VERSION 5.7 ;
BUSBITCHARS "[]" ;
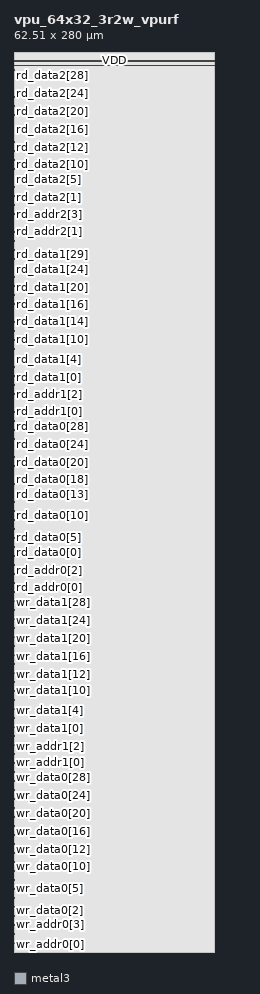
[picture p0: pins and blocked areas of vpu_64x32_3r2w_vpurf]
MACRO vpu_64x32_3r2w_vpurf
  FOREIGN vpu_64x32_3r2w_vpurf 0 0 ;
  SYMMETRY X Y R90 ;
  SIZE 62.510 BY 280.000 ;
  CLASS BLOCK ;
  PIN clk
    DIRECTION INPUT ;
    USE SIGNAL ;
    SHAPE ABUTMENT ;
    PORT
      LAYER metal3 ;
      RECT 0.000 1.400 0.140 1.540 ;
    END
  END clk
  PIN wr_enable0
    DIRECTION INPUT ;
    USE SIGNAL ;
    SHAPE ABUTMENT ;
    PORT
      LAYER metal3 ;
      RECT 0.000 2.800 0.140 2.940 ;
    END
  END wr_enable0
  PIN wr_addr0[0]
    DIRECTION INPUT ;
    USE SIGNAL ;
    SHAPE ABUTMENT ;
    PORT
      LAYER metal3 ;
      RECT 0.000 4.200 0.140 4.340 ;
    END
  END wr_addr0[0]
  PIN wr_addr0[1]
    DIRECTION INPUT ;
    USE SIGNAL ;
    SHAPE ABUTMENT ;
    PORT
      LAYER metal3 ;
      RECT 0.000 5.600 0.140 5.740 ;
    END
  END wr_addr0[1]
  PIN wr_addr0[2]
    DIRECTION INPUT ;
    USE SIGNAL ;
    SHAPE ABUTMENT ;
    PORT
      LAYER metal3 ;
      RECT 0.000 7.000 0.140 7.140 ;
    END
  END wr_addr0[2]
  PIN wr_addr0[3]
    DIRECTION INPUT ;
    USE SIGNAL ;
    SHAPE ABUTMENT ;
    PORT
      LAYER metal3 ;
      RECT 0.000 8.400 0.140 8.540 ;
    END
  END wr_addr0[3]
  PIN wr_addr0[4]
    DIRECTION INPUT ;
    USE SIGNAL ;
    SHAPE ABUTMENT ;
    PORT
      LAYER metal3 ;
      RECT 0.000 9.800 0.140 9.940 ;
    END
  END wr_addr0[4]
  PIN wr_addr0[5]
    DIRECTION INPUT ;
    USE SIGNAL ;
    SHAPE ABUTMENT ;
    PORT
      LAYER metal3 ;
      RECT 0.000 11.200 0.140 11.340 ;
    END
  END wr_addr0[5]
  PIN wr_data0[0]
    DIRECTION INPUT ;
    USE SIGNAL ;
    SHAPE ABUTMENT ;
    PORT
      LAYER metal3 ;
      RECT 0.000 12.600 0.140 12.740 ;
    END
  END wr_data0[0]
  PIN wr_data0[1]
    DIRECTION INPUT ;
    USE SIGNAL ;
    SHAPE ABUTMENT ;
    PORT
      LAYER metal3 ;
      RECT 0.000 14.000 0.140 14.140 ;
    END
  END wr_data0[1]
  PIN wr_data0[2]
    DIRECTION INPUT ;
    USE SIGNAL ;
    SHAPE ABUTMENT ;
    PORT
      LAYER metal3 ;
      RECT 0.000 15.400 0.140 15.540 ;
    END
  END wr_data0[2]
  PIN wr_data0[3]
    DIRECTION INPUT ;
    USE SIGNAL ;
    SHAPE ABUTMENT ;
    PORT
      LAYER metal3 ;
      RECT 0.000 16.800 0.140 16.940 ;
    END
  END wr_data0[3]
  PIN wr_data0[4]
    DIRECTION INPUT ;
    USE SIGNAL ;
    SHAPE ABUTMENT ;
    PORT
      LAYER metal3 ;
      RECT 0.000 18.200 0.140 18.340 ;
    END
  END wr_data0[4]
  PIN wr_data0[5]
    DIRECTION INPUT ;
    USE SIGNAL ;
    SHAPE ABUTMENT ;
    PORT
      LAYER metal3 ;
      RECT 0.000 19.600 0.140 19.740 ;
    END
  END wr_data0[5]
  PIN wr_data0[6]
    DIRECTION INPUT ;
    USE SIGNAL ;
    SHAPE ABUTMENT ;
    PORT
      LAYER metal3 ;
      RECT 0.000 21.000 0.140 21.140 ;
    END
  END wr_data0[6]
  PIN wr_data0[7]
    DIRECTION INPUT ;
    USE SIGNAL ;
    SHAPE ABUTMENT ;
    PORT
      LAYER metal3 ;
      RECT 0.000 22.400 0.140 22.540 ;
    END
  END wr_data0[7]
  PIN wr_data0[8]
    DIRECTION INPUT ;
    USE SIGNAL ;
    SHAPE ABUTMENT ;
    PORT
      LAYER metal3 ;
      RECT 0.000 23.800 0.140 23.940 ;
    END
  END wr_data0[8]
  PIN wr_data0[9]
    DIRECTION INPUT ;
    USE SIGNAL ;
    SHAPE ABUTMENT ;
    PORT
      LAYER metal3 ;
      RECT 0.000 25.200 0.140 25.340 ;
    END
  END wr_data0[9]
  PIN wr_data0[10]
    DIRECTION INPUT ;
    USE SIGNAL ;
    SHAPE ABUTMENT ;
    PORT
      LAYER metal3 ;
      RECT 0.000 26.600 0.140 26.740 ;
    END
  END wr_data0[10]
  PIN wr_data0[11]
    DIRECTION INPUT ;
    USE SIGNAL ;
    SHAPE ABUTMENT ;
    PORT
      LAYER metal3 ;
      RECT 0.000 28.000 0.140 28.140 ;
    END
  END wr_data0[11]
  PIN wr_data0[12]
    DIRECTION INPUT ;
    USE SIGNAL ;
    SHAPE ABUTMENT ;
    PORT
      LAYER metal3 ;
      RECT 0.000 29.400 0.140 29.540 ;
    END
  END wr_data0[12]
  PIN wr_data0[13]
    DIRECTION INPUT ;
    USE SIGNAL ;
    SHAPE ABUTMENT ;
    PORT
      LAYER metal3 ;
      RECT 0.000 30.800 0.140 30.940 ;
    END
  END wr_data0[13]
  PIN wr_data0[14]
    DIRECTION INPUT ;
    USE SIGNAL ;
    SHAPE ABUTMENT ;
    PORT
      LAYER metal3 ;
      RECT 0.000 32.200 0.140 32.340 ;
    END
  END wr_data0[14]
  PIN wr_data0[15]
    DIRECTION INPUT ;
    USE SIGNAL ;
    SHAPE ABUTMENT ;
    PORT
      LAYER metal3 ;
      RECT 0.000 33.600 0.140 33.740 ;
    END
  END wr_data0[15]
  PIN wr_data0[16]
    DIRECTION INPUT ;
    USE SIGNAL ;
    SHAPE ABUTMENT ;
    PORT
      LAYER metal3 ;
      RECT 0.000 35.000 0.140 35.140 ;
    END
  END wr_data0[16]
  PIN wr_data0[17]
    DIRECTION INPUT ;
    USE SIGNAL ;
    SHAPE ABUTMENT ;
    PORT
      LAYER metal3 ;
      RECT 0.000 36.400 0.140 36.540 ;
    END
  END wr_data0[17]
  PIN wr_data0[18]
    DIRECTION INPUT ;
    USE SIGNAL ;
    SHAPE ABUTMENT ;
    PORT
      LAYER metal3 ;
      RECT 0.000 37.800 0.140 37.940 ;
    END
  END wr_data0[18]
  PIN wr_data0[19]
    DIRECTION INPUT ;
    USE SIGNAL ;
    SHAPE ABUTMENT ;
    PORT
      LAYER metal3 ;
      RECT 0.000 39.200 0.140 39.340 ;
    END
  END wr_data0[19]
  PIN wr_data0[20]
    DIRECTION INPUT ;
    USE SIGNAL ;
    SHAPE ABUTMENT ;
    PORT
      LAYER metal3 ;
      RECT 0.000 40.600 0.140 40.740 ;
    END
  END wr_data0[20]
  PIN wr_data0[21]
    DIRECTION INPUT ;
    USE SIGNAL ;
    SHAPE ABUTMENT ;
    PORT
      LAYER metal3 ;
      RECT 0.000 42.000 0.140 42.140 ;
    END
  END wr_data0[21]
  PIN wr_data0[22]
    DIRECTION INPUT ;
    USE SIGNAL ;
    SHAPE ABUTMENT ;
    PORT
      LAYER metal3 ;
      RECT 0.000 43.400 0.140 43.540 ;
    END
  END wr_data0[22]
  PIN wr_data0[23]
    DIRECTION INPUT ;
    USE SIGNAL ;
    SHAPE ABUTMENT ;
    PORT
      LAYER metal3 ;
      RECT 0.000 44.800 0.140 44.940 ;
    END
  END wr_data0[23]
  PIN wr_data0[24]
    DIRECTION INPUT ;
    USE SIGNAL ;
    SHAPE ABUTMENT ;
    PORT
      LAYER metal3 ;
      RECT 0.000 46.200 0.140 46.340 ;
    END
  END wr_data0[24]
  PIN wr_data0[25]
    DIRECTION INPUT ;
    USE SIGNAL ;
    SHAPE ABUTMENT ;
    PORT
      LAYER metal3 ;
      RECT 0.000 47.600 0.140 47.740 ;
    END
  END wr_data0[25]
  PIN wr_data0[26]
    DIRECTION INPUT ;
    USE SIGNAL ;
    SHAPE ABUTMENT ;
    PORT
      LAYER metal3 ;
      RECT 0.000 49.000 0.140 49.140 ;
    END
  END wr_data0[26]
  PIN wr_data0[27]
    DIRECTION INPUT ;
    USE SIGNAL ;
    SHAPE ABUTMENT ;
    PORT
      LAYER metal3 ;
      RECT 0.000 50.400 0.140 50.540 ;
    END
  END wr_data0[27]
  PIN wr_data0[28]
    DIRECTION INPUT ;
    USE SIGNAL ;
    SHAPE ABUTMENT ;
    PORT
      LAYER metal3 ;
      RECT 0.000 51.800 0.140 51.940 ;
    END
  END wr_data0[28]
  PIN wr_data0[29]
    DIRECTION INPUT ;
    USE SIGNAL ;
    SHAPE ABUTMENT ;
    PORT
      LAYER metal3 ;
      RECT 0.000 53.200 0.140 53.340 ;
    END
  END wr_data0[29]
  PIN wr_data0[30]
    DIRECTION INPUT ;
    USE SIGNAL ;
    SHAPE ABUTMENT ;
    PORT
      LAYER metal3 ;
      RECT 0.000 54.600 0.140 54.740 ;
    END
  END wr_data0[30]
  PIN wr_data0[31]
    DIRECTION INPUT ;
    USE SIGNAL ;
    SHAPE ABUTMENT ;
    PORT
      LAYER metal3 ;
      RECT 0.000 56.000 0.140 56.140 ;
    END
  END wr_data0[31]
  PIN wr_enable1
    DIRECTION INPUT ;
    USE SIGNAL ;
    SHAPE ABUTMENT ;
    PORT
      LAYER metal3 ;
      RECT 0.000 57.400 0.140 57.540 ;
    END
  END wr_enable1
  PIN wr_addr1[0]
    DIRECTION INPUT ;
    USE SIGNAL ;
    SHAPE ABUTMENT ;
    PORT
      LAYER metal3 ;
      RECT 0.000 58.800 0.140 58.940 ;
    END
  END wr_addr1[0]
  PIN wr_addr1[1]
    DIRECTION INPUT ;
    USE SIGNAL ;
    SHAPE ABUTMENT ;
    PORT
      LAYER metal3 ;
      RECT 0.000 60.200 0.140 60.340 ;
    END
  END wr_addr1[1]
  PIN wr_addr1[2]
    DIRECTION INPUT ;
    USE SIGNAL ;
    SHAPE ABUTMENT ;
    PORT
      LAYER metal3 ;
      RECT 0.000 61.600 0.140 61.740 ;
    END
  END wr_addr1[2]
  PIN wr_addr1[3]
    DIRECTION INPUT ;
    USE SIGNAL ;
    SHAPE ABUTMENT ;
    PORT
      LAYER metal3 ;
      RECT 0.000 63.000 0.140 63.140 ;
    END
  END wr_addr1[3]
  PIN wr_addr1[4]
    DIRECTION INPUT ;
    USE SIGNAL ;
    SHAPE ABUTMENT ;
    PORT
      LAYER metal3 ;
      RECT 0.000 64.400 0.140 64.540 ;
    END
  END wr_addr1[4]
  PIN wr_addr1[5]
    DIRECTION INPUT ;
    USE SIGNAL ;
    SHAPE ABUTMENT ;
    PORT
      LAYER metal3 ;
      RECT 0.000 65.800 0.140 65.940 ;
    END
  END wr_addr1[5]
  PIN wr_data1[0]
    DIRECTION INPUT ;
    USE SIGNAL ;
    SHAPE ABUTMENT ;
    PORT
      LAYER metal3 ;
      RECT 0.000 67.200 0.140 67.340 ;
    END
  END wr_data1[0]
  PIN wr_data1[1]
    DIRECTION INPUT ;
    USE SIGNAL ;
    SHAPE ABUTMENT ;
    PORT
      LAYER metal3 ;
      RECT 0.000 68.600 0.140 68.740 ;
    END
  END wr_data1[1]
  PIN wr_data1[2]
    DIRECTION INPUT ;
    USE SIGNAL ;
    SHAPE ABUTMENT ;
    PORT
      LAYER metal3 ;
      RECT 0.000 70.000 0.140 70.140 ;
    END
  END wr_data1[2]
  PIN wr_data1[3]
    DIRECTION INPUT ;
    USE SIGNAL ;
    SHAPE ABUTMENT ;
    PORT
      LAYER metal3 ;
      RECT 0.000 71.400 0.140 71.540 ;
    END
  END wr_data1[3]
  PIN wr_data1[4]
    DIRECTION INPUT ;
    USE SIGNAL ;
    SHAPE ABUTMENT ;
    PORT
      LAYER metal3 ;
      RECT 0.000 72.800 0.140 72.940 ;
    END
  END wr_data1[4]
  PIN wr_data1[5]
    DIRECTION INPUT ;
    USE SIGNAL ;
    SHAPE ABUTMENT ;
    PORT
      LAYER metal3 ;
      RECT 0.000 74.200 0.140 74.340 ;
    END
  END wr_data1[5]
  PIN wr_data1[6]
    DIRECTION INPUT ;
    USE SIGNAL ;
    SHAPE ABUTMENT ;
    PORT
      LAYER metal3 ;
      RECT 0.000 75.600 0.140 75.740 ;
    END
  END wr_data1[6]
  PIN wr_data1[7]
    DIRECTION INPUT ;
    USE SIGNAL ;
    SHAPE ABUTMENT ;
    PORT
      LAYER metal3 ;
      RECT 0.000 77.000 0.140 77.140 ;
    END
  END wr_data1[7]
  PIN wr_data1[8]
    DIRECTION INPUT ;
    USE SIGNAL ;
    SHAPE ABUTMENT ;
    PORT
      LAYER metal3 ;
      RECT 0.000 78.400 0.140 78.540 ;
    END
  END wr_data1[8]
  PIN wr_data1[9]
    DIRECTION INPUT ;
    USE SIGNAL ;
    SHAPE ABUTMENT ;
    PORT
      LAYER metal3 ;
      RECT 0.000 79.800 0.140 79.940 ;
    END
  END wr_data1[9]
  PIN wr_data1[10]
    DIRECTION INPUT ;
    USE SIGNAL ;
    SHAPE ABUTMENT ;
    PORT
      LAYER metal3 ;
      RECT 0.000 81.200 0.140 81.340 ;
    END
  END wr_data1[10]
  PIN wr_data1[11]
    DIRECTION INPUT ;
    USE SIGNAL ;
    SHAPE ABUTMENT ;
    PORT
      LAYER metal3 ;
      RECT 0.000 82.600 0.140 82.740 ;
    END
  END wr_data1[11]
  PIN wr_data1[12]
    DIRECTION INPUT ;
    USE SIGNAL ;
    SHAPE ABUTMENT ;
    PORT
      LAYER metal3 ;
      RECT 0.000 84.000 0.140 84.140 ;
    END
  END wr_data1[12]
  PIN wr_data1[13]
    DIRECTION INPUT ;
    USE SIGNAL ;
    SHAPE ABUTMENT ;
    PORT
      LAYER metal3 ;
      RECT 0.000 85.400 0.140 85.540 ;
    END
  END wr_data1[13]
  PIN wr_data1[14]
    DIRECTION INPUT ;
    USE SIGNAL ;
    SHAPE ABUTMENT ;
    PORT
      LAYER metal3 ;
      RECT 0.000 86.800 0.140 86.940 ;
    END
  END wr_data1[14]
  PIN wr_data1[15]
    DIRECTION INPUT ;
    USE SIGNAL ;
    SHAPE ABUTMENT ;
    PORT
      LAYER metal3 ;
      RECT 0.000 88.200 0.140 88.340 ;
    END
  END wr_data1[15]
  PIN wr_data1[16]
    DIRECTION INPUT ;
    USE SIGNAL ;
    SHAPE ABUTMENT ;
    PORT
      LAYER metal3 ;
      RECT 0.000 89.600 0.140 89.740 ;
    END
  END wr_data1[16]
  PIN wr_data1[17]
    DIRECTION INPUT ;
    USE SIGNAL ;
    SHAPE ABUTMENT ;
    PORT
      LAYER metal3 ;
      RECT 0.000 91.000 0.140 91.140 ;
    END
  END wr_data1[17]
  PIN wr_data1[18]
    DIRECTION INPUT ;
    USE SIGNAL ;
    SHAPE ABUTMENT ;
    PORT
      LAYER metal3 ;
      RECT 0.000 92.400 0.140 92.540 ;
    END
  END wr_data1[18]
  PIN wr_data1[19]
    DIRECTION INPUT ;
    USE SIGNAL ;
    SHAPE ABUTMENT ;
    PORT
      LAYER metal3 ;
      RECT 0.000 93.800 0.140 93.940 ;
    END
  END wr_data1[19]
  PIN wr_data1[20]
    DIRECTION INPUT ;
    USE SIGNAL ;
    SHAPE ABUTMENT ;
    PORT
      LAYER metal3 ;
      RECT 0.000 95.200 0.140 95.340 ;
    END
  END wr_data1[20]
  PIN wr_data1[21]
    DIRECTION INPUT ;
    USE SIGNAL ;
    SHAPE ABUTMENT ;
    PORT
      LAYER metal3 ;
      RECT 0.000 96.600 0.140 96.740 ;
    END
  END wr_data1[21]
  PIN wr_data1[22]
    DIRECTION INPUT ;
    USE SIGNAL ;
    SHAPE ABUTMENT ;
    PORT
      LAYER metal3 ;
      RECT 0.000 98.000 0.140 98.140 ;
    END
  END wr_data1[22]
  PIN wr_data1[23]
    DIRECTION INPUT ;
    USE SIGNAL ;
    SHAPE ABUTMENT ;
    PORT
      LAYER metal3 ;
      RECT 0.000 99.400 0.140 99.540 ;
    END
  END wr_data1[23]
  PIN wr_data1[24]
    DIRECTION INPUT ;
    USE SIGNAL ;
    SHAPE ABUTMENT ;
    PORT
      LAYER metal3 ;
      RECT 0.000 100.800 0.140 100.940 ;
    END
  END wr_data1[24]
  PIN wr_data1[25]
    DIRECTION INPUT ;
    USE SIGNAL ;
    SHAPE ABUTMENT ;
    PORT
      LAYER metal3 ;
      RECT 0.000 102.200 0.140 102.340 ;
    END
  END wr_data1[25]
  PIN wr_data1[26]
    DIRECTION INPUT ;
    USE SIGNAL ;
    SHAPE ABUTMENT ;
    PORT
      LAYER metal3 ;
      RECT 0.000 103.600 0.140 103.740 ;
    END
  END wr_data1[26]
  PIN wr_data1[27]
    DIRECTION INPUT ;
    USE SIGNAL ;
    SHAPE ABUTMENT ;
    PORT
      LAYER metal3 ;
      RECT 0.000 105.000 0.140 105.140 ;
    END
  END wr_data1[27]
  PIN wr_data1[28]
    DIRECTION INPUT ;
    USE SIGNAL ;
    SHAPE ABUTMENT ;
    PORT
      LAYER metal3 ;
      RECT 0.000 106.400 0.140 106.540 ;
    END
  END wr_data1[28]
  PIN wr_data1[29]
    DIRECTION INPUT ;
    USE SIGNAL ;
    SHAPE ABUTMENT ;
    PORT
      LAYER metal3 ;
      RECT 0.000 107.800 0.140 107.940 ;
    END
  END wr_data1[29]
  PIN wr_data1[30]
    DIRECTION INPUT ;
    USE SIGNAL ;
    SHAPE ABUTMENT ;
    PORT
      LAYER metal3 ;
      RECT 0.000 109.200 0.140 109.340 ;
    END
  END wr_data1[30]
  PIN wr_data1[31]
    DIRECTION INPUT ;
    USE SIGNAL ;
    SHAPE ABUTMENT ;
    PORT
      LAYER metal3 ;
      RECT 0.000 110.600 0.140 110.740 ;
    END
  END wr_data1[31]
  PIN rd_enable0
    DIRECTION INPUT ;
    USE SIGNAL ;
    SHAPE ABUTMENT ;
    PORT
      LAYER metal3 ;
      RECT 0.000 112.000 0.140 112.140 ;
    END
  END rd_enable0
  PIN rd_addr0[0]
    DIRECTION INPUT ;
    USE SIGNAL ;
    SHAPE ABUTMENT ;
    PORT
      LAYER metal3 ;
      RECT 0.000 113.400 0.140 113.540 ;
    END
  END rd_addr0[0]
  PIN rd_addr0[1]
    DIRECTION INPUT ;
    USE SIGNAL ;
    SHAPE ABUTMENT ;
    PORT
      LAYER metal3 ;
      RECT 0.000 114.800 0.140 114.940 ;
    END
  END rd_addr0[1]
  PIN rd_addr0[2]
    DIRECTION INPUT ;
    USE SIGNAL ;
    SHAPE ABUTMENT ;
    PORT
      LAYER metal3 ;
      RECT 0.000 116.200 0.140 116.340 ;
    END
  END rd_addr0[2]
  PIN rd_addr0[3]
    DIRECTION INPUT ;
    USE SIGNAL ;
    SHAPE ABUTMENT ;
    PORT
      LAYER metal3 ;
      RECT 0.000 117.600 0.140 117.740 ;
    END
  END rd_addr0[3]
  PIN rd_addr0[4]
    DIRECTION INPUT ;
    USE SIGNAL ;
    SHAPE ABUTMENT ;
    PORT
      LAYER metal3 ;
      RECT 0.000 119.000 0.140 119.140 ;
    END
  END rd_addr0[4]
  PIN rd_addr0[5]
    DIRECTION INPUT ;
    USE SIGNAL ;
    SHAPE ABUTMENT ;
    PORT
      LAYER metal3 ;
      RECT 0.000 120.400 0.140 120.540 ;
    END
  END rd_addr0[5]
  PIN rd_data0[0]
    DIRECTION OUTPUT ;
    USE SIGNAL ;
    SHAPE ABUTMENT ;
    PORT
      LAYER metal3 ;
      RECT 0.000 121.800 0.140 121.940 ;
    END
  END rd_data0[0]
  PIN rd_data0[1]
    DIRECTION OUTPUT ;
    USE SIGNAL ;
    SHAPE ABUTMENT ;
    PORT
      LAYER metal3 ;
      RECT 0.000 123.200 0.140 123.340 ;
    END
  END rd_data0[1]
  PIN rd_data0[2]
    DIRECTION OUTPUT ;
    USE SIGNAL ;
    SHAPE ABUTMENT ;
    PORT
      LAYER metal3 ;
      RECT 0.000 124.600 0.140 124.740 ;
    END
  END rd_data0[2]
  PIN rd_data0[3]
    DIRECTION OUTPUT ;
    USE SIGNAL ;
    SHAPE ABUTMENT ;
    PORT
      LAYER metal3 ;
      RECT 0.000 126.000 0.140 126.140 ;
    END
  END rd_data0[3]
  PIN rd_data0[4]
    DIRECTION OUTPUT ;
    USE SIGNAL ;
    SHAPE ABUTMENT ;
    PORT
      LAYER metal3 ;
      RECT 0.000 127.400 0.140 127.540 ;
    END
  END rd_data0[4]
  PIN rd_data0[5]
    DIRECTION OUTPUT ;
    USE SIGNAL ;
    SHAPE ABUTMENT ;
    PORT
      LAYER metal3 ;
      RECT 0.000 128.800 0.140 128.940 ;
    END
  END rd_data0[5]
  PIN rd_data0[6]
    DIRECTION OUTPUT ;
    USE SIGNAL ;
    SHAPE ABUTMENT ;
    PORT
      LAYER metal3 ;
      RECT 0.000 130.200 0.140 130.340 ;
    END
  END rd_data0[6]
  PIN rd_data0[7]
    DIRECTION OUTPUT ;
    USE SIGNAL ;
    SHAPE ABUTMENT ;
    PORT
      LAYER metal3 ;
      RECT 0.000 131.600 0.140 131.740 ;
    END
  END rd_data0[7]
  PIN rd_data0[8]
    DIRECTION OUTPUT ;
    USE SIGNAL ;
    SHAPE ABUTMENT ;
    PORT
      LAYER metal3 ;
      RECT 0.000 133.000 0.140 133.140 ;
    END
  END rd_data0[8]
  PIN rd_data0[9]
    DIRECTION OUTPUT ;
    USE SIGNAL ;
    SHAPE ABUTMENT ;
    PORT
      LAYER metal3 ;
      RECT 0.000 134.400 0.140 134.540 ;
    END
  END rd_data0[9]
  PIN rd_data0[10]
    DIRECTION OUTPUT ;
    USE SIGNAL ;
    SHAPE ABUTMENT ;
    PORT
      LAYER metal3 ;
      RECT 0.000 135.800 0.140 135.940 ;
    END
  END rd_data0[10]
  PIN rd_data0[11]
    DIRECTION OUTPUT ;
    USE SIGNAL ;
    SHAPE ABUTMENT ;
    PORT
      LAYER metal3 ;
      RECT 0.000 137.200 0.140 137.340 ;
    END
  END rd_data0[11]
  PIN rd_data0[12]
    DIRECTION OUTPUT ;
    USE SIGNAL ;
    SHAPE ABUTMENT ;
    PORT
      LAYER metal3 ;
      RECT 0.000 138.600 0.140 138.740 ;
    END
  END rd_data0[12]
  PIN rd_data0[13]
    DIRECTION OUTPUT ;
    USE SIGNAL ;
    SHAPE ABUTMENT ;
    PORT
      LAYER metal3 ;
      RECT 0.000 140.000 0.140 140.140 ;
    END
  END rd_data0[13]
  PIN rd_data0[14]
    DIRECTION OUTPUT ;
    USE SIGNAL ;
    SHAPE ABUTMENT ;
    PORT
      LAYER metal3 ;
      RECT 0.000 141.400 0.140 141.540 ;
    END
  END rd_data0[14]
  PIN rd_data0[15]
    DIRECTION OUTPUT ;
    USE SIGNAL ;
    SHAPE ABUTMENT ;
    PORT
      LAYER metal3 ;
      RECT 0.000 142.800 0.140 142.940 ;
    END
  END rd_data0[15]
  PIN rd_data0[16]
    DIRECTION OUTPUT ;
    USE SIGNAL ;
    SHAPE ABUTMENT ;
    PORT
      LAYER metal3 ;
      RECT 0.000 144.200 0.140 144.340 ;
    END
  END rd_data0[16]
  PIN rd_data0[17]
    DIRECTION OUTPUT ;
    USE SIGNAL ;
    SHAPE ABUTMENT ;
    PORT
      LAYER metal3 ;
      RECT 0.000 145.600 0.140 145.740 ;
    END
  END rd_data0[17]
  PIN rd_data0[18]
    DIRECTION OUTPUT ;
    USE SIGNAL ;
    SHAPE ABUTMENT ;
    PORT
      LAYER metal3 ;
      RECT 0.000 147.000 0.140 147.140 ;
    END
  END rd_data0[18]
  PIN rd_data0[19]
    DIRECTION OUTPUT ;
    USE SIGNAL ;
    SHAPE ABUTMENT ;
    PORT
      LAYER metal3 ;
      RECT 0.000 148.400 0.140 148.540 ;
    END
  END rd_data0[19]
  PIN rd_data0[20]
    DIRECTION OUTPUT ;
    USE SIGNAL ;
    SHAPE ABUTMENT ;
    PORT
      LAYER metal3 ;
      RECT 0.000 149.800 0.140 149.940 ;
    END
  END rd_data0[20]
  PIN rd_data0[21]
    DIRECTION OUTPUT ;
    USE SIGNAL ;
    SHAPE ABUTMENT ;
    PORT
      LAYER metal3 ;
      RECT 0.000 151.200 0.140 151.340 ;
    END
  END rd_data0[21]
  PIN rd_data0[22]
    DIRECTION OUTPUT ;
    USE SIGNAL ;
    SHAPE ABUTMENT ;
    PORT
      LAYER metal3 ;
      RECT 0.000 152.600 0.140 152.740 ;
    END
  END rd_data0[22]
  PIN rd_data0[23]
    DIRECTION OUTPUT ;
    USE SIGNAL ;
    SHAPE ABUTMENT ;
    PORT
      LAYER metal3 ;
      RECT 0.000 154.000 0.140 154.140 ;
    END
  END rd_data0[23]
  PIN rd_data0[24]
    DIRECTION OUTPUT ;
    USE SIGNAL ;
    SHAPE ABUTMENT ;
    PORT
      LAYER metal3 ;
      RECT 0.000 155.400 0.140 155.540 ;
    END
  END rd_data0[24]
  PIN rd_data0[25]
    DIRECTION OUTPUT ;
    USE SIGNAL ;
    SHAPE ABUTMENT ;
    PORT
      LAYER metal3 ;
      RECT 0.000 156.800 0.140 156.940 ;
    END
  END rd_data0[25]
  PIN rd_data0[26]
    DIRECTION OUTPUT ;
    USE SIGNAL ;
    SHAPE ABUTMENT ;
    PORT
      LAYER metal3 ;
      RECT 0.000 158.200 0.140 158.340 ;
    END
  END rd_data0[26]
  PIN rd_data0[27]
    DIRECTION OUTPUT ;
    USE SIGNAL ;
    SHAPE ABUTMENT ;
    PORT
      LAYER metal3 ;
      RECT 0.000 159.600 0.140 159.740 ;
    END
  END rd_data0[27]
  PIN rd_data0[28]
    DIRECTION OUTPUT ;
    USE SIGNAL ;
    SHAPE ABUTMENT ;
    PORT
      LAYER metal3 ;
      RECT 0.000 161.000 0.140 161.140 ;
    END
  END rd_data0[28]
  PIN rd_data0[29]
    DIRECTION OUTPUT ;
    USE SIGNAL ;
    SHAPE ABUTMENT ;
    PORT
      LAYER metal3 ;
      RECT 0.000 162.400 0.140 162.540 ;
    END
  END rd_data0[29]
  PIN rd_data0[30]
    DIRECTION OUTPUT ;
    USE SIGNAL ;
    SHAPE ABUTMENT ;
    PORT
      LAYER metal3 ;
      RECT 0.000 163.800 0.140 163.940 ;
    END
  END rd_data0[30]
  PIN rd_data0[31]
    DIRECTION OUTPUT ;
    USE SIGNAL ;
    SHAPE ABUTMENT ;
    PORT
      LAYER metal3 ;
      RECT 0.000 165.200 0.140 165.340 ;
    END
  END rd_data0[31]
  PIN rd_enable1
    DIRECTION INPUT ;
    USE SIGNAL ;
    SHAPE ABUTMENT ;
    PORT
      LAYER metal3 ;
      RECT 0.000 166.600 0.140 166.740 ;
    END
  END rd_enable1
  PIN rd_addr1[0]
    DIRECTION INPUT ;
    USE SIGNAL ;
    SHAPE ABUTMENT ;
    PORT
      LAYER metal3 ;
      RECT 0.000 168.000 0.140 168.140 ;
    END
  END rd_addr1[0]
  PIN rd_addr1[1]
    DIRECTION INPUT ;
    USE SIGNAL ;
    SHAPE ABUTMENT ;
    PORT
      LAYER metal3 ;
      RECT 0.000 169.400 0.140 169.540 ;
    END
  END rd_addr1[1]
  PIN rd_addr1[2]
    DIRECTION INPUT ;
    USE SIGNAL ;
    SHAPE ABUTMENT ;
    PORT
      LAYER metal3 ;
      RECT 0.000 170.800 0.140 170.940 ;
    END
  END rd_addr1[2]
  PIN rd_addr1[3]
    DIRECTION INPUT ;
    USE SIGNAL ;
    SHAPE ABUTMENT ;
    PORT
      LAYER metal3 ;
      RECT 0.000 172.200 0.140 172.340 ;
    END
  END rd_addr1[3]
  PIN rd_addr1[4]
    DIRECTION INPUT ;
    USE SIGNAL ;
    SHAPE ABUTMENT ;
    PORT
      LAYER metal3 ;
      RECT 0.000 173.600 0.140 173.740 ;
    END
  END rd_addr1[4]
  PIN rd_addr1[5]
    DIRECTION INPUT ;
    USE SIGNAL ;
    SHAPE ABUTMENT ;
    PORT
      LAYER metal3 ;
      RECT 0.000 175.000 0.140 175.140 ;
    END
  END rd_addr1[5]
  PIN rd_data1[0]
    DIRECTION OUTPUT ;
    USE SIGNAL ;
    SHAPE ABUTMENT ;
    PORT
      LAYER metal3 ;
      RECT 0.000 176.400 0.140 176.540 ;
    END
  END rd_data1[0]
  PIN rd_data1[1]
    DIRECTION OUTPUT ;
    USE SIGNAL ;
    SHAPE ABUTMENT ;
    PORT
      LAYER metal3 ;
      RECT 0.000 177.800 0.140 177.940 ;
    END
  END rd_data1[1]
  PIN rd_data1[2]
    DIRECTION OUTPUT ;
    USE SIGNAL ;
    SHAPE ABUTMENT ;
    PORT
      LAYER metal3 ;
      RECT 0.000 179.200 0.140 179.340 ;
    END
  END rd_data1[2]
  PIN rd_data1[3]
    DIRECTION OUTPUT ;
    USE SIGNAL ;
    SHAPE ABUTMENT ;
    PORT
      LAYER metal3 ;
      RECT 0.000 180.600 0.140 180.740 ;
    END
  END rd_data1[3]
  PIN rd_data1[4]
    DIRECTION OUTPUT ;
    USE SIGNAL ;
    SHAPE ABUTMENT ;
    PORT
      LAYER metal3 ;
      RECT 0.000 182.000 0.140 182.140 ;
    END
  END rd_data1[4]
  PIN rd_data1[5]
    DIRECTION OUTPUT ;
    USE SIGNAL ;
    SHAPE ABUTMENT ;
    PORT
      LAYER metal3 ;
      RECT 0.000 183.400 0.140 183.540 ;
    END
  END rd_data1[5]
  PIN rd_data1[6]
    DIRECTION OUTPUT ;
    USE SIGNAL ;
    SHAPE ABUTMENT ;
    PORT
      LAYER metal3 ;
      RECT 0.000 184.800 0.140 184.940 ;
    END
  END rd_data1[6]
  PIN rd_data1[7]
    DIRECTION OUTPUT ;
    USE SIGNAL ;
    SHAPE ABUTMENT ;
    PORT
      LAYER metal3 ;
      RECT 0.000 186.200 0.140 186.340 ;
    END
  END rd_data1[7]
  PIN rd_data1[8]
    DIRECTION OUTPUT ;
    USE SIGNAL ;
    SHAPE ABUTMENT ;
    PORT
      LAYER metal3 ;
      RECT 0.000 187.600 0.140 187.740 ;
    END
  END rd_data1[8]
  PIN rd_data1[9]
    DIRECTION OUTPUT ;
    USE SIGNAL ;
    SHAPE ABUTMENT ;
    PORT
      LAYER metal3 ;
      RECT 0.000 189.000 0.140 189.140 ;
    END
  END rd_data1[9]
  PIN rd_data1[10]
    DIRECTION OUTPUT ;
    USE SIGNAL ;
    SHAPE ABUTMENT ;
    PORT
      LAYER metal3 ;
      RECT 0.000 190.400 0.140 190.540 ;
    END
  END rd_data1[10]
  PIN rd_data1[11]
    DIRECTION OUTPUT ;
    USE SIGNAL ;
    SHAPE ABUTMENT ;
    PORT
      LAYER metal3 ;
      RECT 0.000 191.800 0.140 191.940 ;
    END
  END rd_data1[11]
  PIN rd_data1[12]
    DIRECTION OUTPUT ;
    USE SIGNAL ;
    SHAPE ABUTMENT ;
    PORT
      LAYER metal3 ;
      RECT 0.000 193.200 0.140 193.340 ;
    END
  END rd_data1[12]
  PIN rd_data1[13]
    DIRECTION OUTPUT ;
    USE SIGNAL ;
    SHAPE ABUTMENT ;
    PORT
      LAYER metal3 ;
      RECT 0.000 194.600 0.140 194.740 ;
    END
  END rd_data1[13]
  PIN rd_data1[14]
    DIRECTION OUTPUT ;
    USE SIGNAL ;
    SHAPE ABUTMENT ;
    PORT
      LAYER metal3 ;
      RECT 0.000 196.000 0.140 196.140 ;
    END
  END rd_data1[14]
  PIN rd_data1[15]
    DIRECTION OUTPUT ;
    USE SIGNAL ;
    SHAPE ABUTMENT ;
    PORT
      LAYER metal3 ;
      RECT 0.000 197.400 0.140 197.540 ;
    END
  END rd_data1[15]
  PIN rd_data1[16]
    DIRECTION OUTPUT ;
    USE SIGNAL ;
    SHAPE ABUTMENT ;
    PORT
      LAYER metal3 ;
      RECT 0.000 198.800 0.140 198.940 ;
    END
  END rd_data1[16]
  PIN rd_data1[17]
    DIRECTION OUTPUT ;
    USE SIGNAL ;
    SHAPE ABUTMENT ;
    PORT
      LAYER metal3 ;
      RECT 0.000 200.200 0.140 200.340 ;
    END
  END rd_data1[17]
  PIN rd_data1[18]
    DIRECTION OUTPUT ;
    USE SIGNAL ;
    SHAPE ABUTMENT ;
    PORT
      LAYER metal3 ;
      RECT 0.000 201.600 0.140 201.740 ;
    END
  END rd_data1[18]
  PIN rd_data1[19]
    DIRECTION OUTPUT ;
    USE SIGNAL ;
    SHAPE ABUTMENT ;
    PORT
      LAYER metal3 ;
      RECT 0.000 203.000 0.140 203.140 ;
    END
  END rd_data1[19]
  PIN rd_data1[20]
    DIRECTION OUTPUT ;
    USE SIGNAL ;
    SHAPE ABUTMENT ;
    PORT
      LAYER metal3 ;
      RECT 0.000 204.400 0.140 204.540 ;
    END
  END rd_data1[20]
  PIN rd_data1[21]
    DIRECTION OUTPUT ;
    USE SIGNAL ;
    SHAPE ABUTMENT ;
    PORT
      LAYER metal3 ;
      RECT 0.000 205.800 0.140 205.940 ;
    END
  END rd_data1[21]
  PIN rd_data1[22]
    DIRECTION OUTPUT ;
    USE SIGNAL ;
    SHAPE ABUTMENT ;
    PORT
      LAYER metal3 ;
      RECT 0.000 207.200 0.140 207.340 ;
    END
  END rd_data1[22]
  PIN rd_data1[23]
    DIRECTION OUTPUT ;
    USE SIGNAL ;
    SHAPE ABUTMENT ;
    PORT
      LAYER metal3 ;
      RECT 0.000 208.600 0.140 208.740 ;
    END
  END rd_data1[23]
  PIN rd_data1[24]
    DIRECTION OUTPUT ;
    USE SIGNAL ;
    SHAPE ABUTMENT ;
    PORT
      LAYER metal3 ;
      RECT 0.000 210.000 0.140 210.140 ;
    END
  END rd_data1[24]
  PIN rd_data1[25]
    DIRECTION OUTPUT ;
    USE SIGNAL ;
    SHAPE ABUTMENT ;
    PORT
      LAYER metal3 ;
      RECT 0.000 211.400 0.140 211.540 ;
    END
  END rd_data1[25]
  PIN rd_data1[26]
    DIRECTION OUTPUT ;
    USE SIGNAL ;
    SHAPE ABUTMENT ;
    PORT
      LAYER metal3 ;
      RECT 0.000 212.800 0.140 212.940 ;
    END
  END rd_data1[26]
  PIN rd_data1[27]
    DIRECTION OUTPUT ;
    USE SIGNAL ;
    SHAPE ABUTMENT ;
    PORT
      LAYER metal3 ;
      RECT 0.000 214.200 0.140 214.340 ;
    END
  END rd_data1[27]
  PIN rd_data1[28]
    DIRECTION OUTPUT ;
    USE SIGNAL ;
    SHAPE ABUTMENT ;
    PORT
      LAYER metal3 ;
      RECT 0.000 215.600 0.140 215.740 ;
    END
  END rd_data1[28]
  PIN rd_data1[29]
    DIRECTION OUTPUT ;
    USE SIGNAL ;
    SHAPE ABUTMENT ;
    PORT
      LAYER metal3 ;
      RECT 0.000 217.000 0.140 217.140 ;
    END
  END rd_data1[29]
  PIN rd_data1[30]
    DIRECTION OUTPUT ;
    USE SIGNAL ;
    SHAPE ABUTMENT ;
    PORT
      LAYER metal3 ;
      RECT 0.000 218.400 0.140 218.540 ;
    END
  END rd_data1[30]
  PIN rd_data1[31]
    DIRECTION OUTPUT ;
    USE SIGNAL ;
    SHAPE ABUTMENT ;
    PORT
      LAYER metal3 ;
      RECT 0.000 219.800 0.140 219.940 ;
    END
  END rd_data1[31]
  PIN rd_enable2
    DIRECTION INPUT ;
    USE SIGNAL ;
    SHAPE ABUTMENT ;
    PORT
      LAYER metal3 ;
      RECT 0.000 221.200 0.140 221.340 ;
    END
  END rd_enable2
  PIN rd_addr2[0]
    DIRECTION INPUT ;
    USE SIGNAL ;
    SHAPE ABUTMENT ;
    PORT
      LAYER metal3 ;
      RECT 0.000 222.600 0.140 222.740 ;
    END
  END rd_addr2[0]
  PIN rd_addr2[1]
    DIRECTION INPUT ;
    USE SIGNAL ;
    SHAPE ABUTMENT ;
    PORT
      LAYER metal3 ;
      RECT 0.000 224.000 0.140 224.140 ;
    END
  END rd_addr2[1]
  PIN rd_addr2[2]
    DIRECTION INPUT ;
    USE SIGNAL ;
    SHAPE ABUTMENT ;
    PORT
      LAYER metal3 ;
      RECT 0.000 225.400 0.140 225.540 ;
    END
  END rd_addr2[2]
  PIN rd_addr2[3]
    DIRECTION INPUT ;
    USE SIGNAL ;
    SHAPE ABUTMENT ;
    PORT
      LAYER metal3 ;
      RECT 0.000 226.800 0.140 226.940 ;
    END
  END rd_addr2[3]
  PIN rd_addr2[4]
    DIRECTION INPUT ;
    USE SIGNAL ;
    SHAPE ABUTMENT ;
    PORT
      LAYER metal3 ;
      RECT 0.000 228.200 0.140 228.340 ;
    END
  END rd_addr2[4]
  PIN rd_addr2[5]
    DIRECTION INPUT ;
    USE SIGNAL ;
    SHAPE ABUTMENT ;
    PORT
      LAYER metal3 ;
      RECT 0.000 229.600 0.140 229.740 ;
    END
  END rd_addr2[5]
  PIN rd_data2[0]
    DIRECTION OUTPUT ;
    USE SIGNAL ;
    SHAPE ABUTMENT ;
    PORT
      LAYER metal3 ;
      RECT 0.000 231.000 0.140 231.140 ;
    END
  END rd_data2[0]
  PIN rd_data2[1]
    DIRECTION OUTPUT ;
    USE SIGNAL ;
    SHAPE ABUTMENT ;
    PORT
      LAYER metal3 ;
      RECT 0.000 232.400 0.140 232.540 ;
    END
  END rd_data2[1]
  PIN rd_data2[2]
    DIRECTION OUTPUT ;
    USE SIGNAL ;
    SHAPE ABUTMENT ;
    PORT
      LAYER metal3 ;
      RECT 0.000 233.800 0.140 233.940 ;
    END
  END rd_data2[2]
  PIN rd_data2[3]
    DIRECTION OUTPUT ;
    USE SIGNAL ;
    SHAPE ABUTMENT ;
    PORT
      LAYER metal3 ;
      RECT 0.000 235.200 0.140 235.340 ;
    END
  END rd_data2[3]
  PIN rd_data2[4]
    DIRECTION OUTPUT ;
    USE SIGNAL ;
    SHAPE ABUTMENT ;
    PORT
      LAYER metal3 ;
      RECT 0.000 236.600 0.140 236.740 ;
    END
  END rd_data2[4]
  PIN rd_data2[5]
    DIRECTION OUTPUT ;
    USE SIGNAL ;
    SHAPE ABUTMENT ;
    PORT
      LAYER metal3 ;
      RECT 0.000 238.000 0.140 238.140 ;
    END
  END rd_data2[5]
  PIN rd_data2[6]
    DIRECTION OUTPUT ;
    USE SIGNAL ;
    SHAPE ABUTMENT ;
    PORT
      LAYER metal3 ;
      RECT 0.000 239.400 0.140 239.540 ;
    END
  END rd_data2[6]
  PIN rd_data2[7]
    DIRECTION OUTPUT ;
    USE SIGNAL ;
    SHAPE ABUTMENT ;
    PORT
      LAYER metal3 ;
      RECT 0.000 240.800 0.140 240.940 ;
    END
  END rd_data2[7]
  PIN rd_data2[8]
    DIRECTION OUTPUT ;
    USE SIGNAL ;
    SHAPE ABUTMENT ;
    PORT
      LAYER metal3 ;
      RECT 0.000 242.200 0.140 242.340 ;
    END
  END rd_data2[8]
  PIN rd_data2[9]
    DIRECTION OUTPUT ;
    USE SIGNAL ;
    SHAPE ABUTMENT ;
    PORT
      LAYER metal3 ;
      RECT 0.000 243.600 0.140 243.740 ;
    END
  END rd_data2[9]
  PIN rd_data2[10]
    DIRECTION OUTPUT ;
    USE SIGNAL ;
    SHAPE ABUTMENT ;
    PORT
      LAYER metal3 ;
      RECT 0.000 245.000 0.140 245.140 ;
    END
  END rd_data2[10]
  PIN rd_data2[11]
    DIRECTION OUTPUT ;
    USE SIGNAL ;
    SHAPE ABUTMENT ;
    PORT
      LAYER metal3 ;
      RECT 0.000 246.400 0.140 246.540 ;
    END
  END rd_data2[11]
  PIN rd_data2[12]
    DIRECTION OUTPUT ;
    USE SIGNAL ;
    SHAPE ABUTMENT ;
    PORT
      LAYER metal3 ;
      RECT 0.000 247.800 0.140 247.940 ;
    END
  END rd_data2[12]
  PIN rd_data2[13]
    DIRECTION OUTPUT ;
    USE SIGNAL ;
    SHAPE ABUTMENT ;
    PORT
      LAYER metal3 ;
      RECT 0.000 249.200 0.140 249.340 ;
    END
  END rd_data2[13]
  PIN rd_data2[14]
    DIRECTION OUTPUT ;
    USE SIGNAL ;
    SHAPE ABUTMENT ;
    PORT
      LAYER metal3 ;
      RECT 0.000 250.600 0.140 250.740 ;
    END
  END rd_data2[14]
  PIN rd_data2[15]
    DIRECTION OUTPUT ;
    USE SIGNAL ;
    SHAPE ABUTMENT ;
    PORT
      LAYER metal3 ;
      RECT 0.000 252.000 0.140 252.140 ;
    END
  END rd_data2[15]
  PIN rd_data2[16]
    DIRECTION OUTPUT ;
    USE SIGNAL ;
    SHAPE ABUTMENT ;
    PORT
      LAYER metal3 ;
      RECT 0.000 253.400 0.140 253.540 ;
    END
  END rd_data2[16]
  PIN rd_data2[17]
    DIRECTION OUTPUT ;
    USE SIGNAL ;
    SHAPE ABUTMENT ;
    PORT
      LAYER metal3 ;
      RECT 0.000 254.800 0.140 254.940 ;
    END
  END rd_data2[17]
  PIN rd_data2[18]
    DIRECTION OUTPUT ;
    USE SIGNAL ;
    SHAPE ABUTMENT ;
    PORT
      LAYER metal3 ;
      RECT 0.000 256.200 0.140 256.340 ;
    END
  END rd_data2[18]
  PIN rd_data2[19]
    DIRECTION OUTPUT ;
    USE SIGNAL ;
    SHAPE ABUTMENT ;
    PORT
      LAYER metal3 ;
      RECT 0.000 257.600 0.140 257.740 ;
    END
  END rd_data2[19]
  PIN rd_data2[20]
    DIRECTION OUTPUT ;
    USE SIGNAL ;
    SHAPE ABUTMENT ;
    PORT
      LAYER metal3 ;
      RECT 0.000 259.000 0.140 259.140 ;
    END
  END rd_data2[20]
  PIN rd_data2[21]
    DIRECTION OUTPUT ;
    USE SIGNAL ;
    SHAPE ABUTMENT ;
    PORT
      LAYER metal3 ;
      RECT 0.000 260.400 0.140 260.540 ;
    END
  END rd_data2[21]
  PIN rd_data2[22]
    DIRECTION OUTPUT ;
    USE SIGNAL ;
    SHAPE ABUTMENT ;
    PORT
      LAYER metal3 ;
      RECT 0.000 261.800 0.140 261.940 ;
    END
  END rd_data2[22]
  PIN rd_data2[23]
    DIRECTION OUTPUT ;
    USE SIGNAL ;
    SHAPE ABUTMENT ;
    PORT
      LAYER metal3 ;
      RECT 0.000 263.200 0.140 263.340 ;
    END
  END rd_data2[23]
  PIN rd_data2[24]
    DIRECTION OUTPUT ;
    USE SIGNAL ;
    SHAPE ABUTMENT ;
    PORT
      LAYER metal3 ;
      RECT 0.000 264.600 0.140 264.740 ;
    END
  END rd_data2[24]
  PIN rd_data2[25]
    DIRECTION OUTPUT ;
    USE SIGNAL ;
    SHAPE ABUTMENT ;
    PORT
      LAYER metal3 ;
      RECT 0.000 266.000 0.140 266.140 ;
    END
  END rd_data2[25]
  PIN rd_data2[26]
    DIRECTION OUTPUT ;
    USE SIGNAL ;
    SHAPE ABUTMENT ;
    PORT
      LAYER metal3 ;
      RECT 0.000 267.400 0.140 267.540 ;
    END
  END rd_data2[26]
  PIN rd_data2[27]
    DIRECTION OUTPUT ;
    USE SIGNAL ;
    SHAPE ABUTMENT ;
    PORT
      LAYER metal3 ;
      RECT 0.000 268.800 0.140 268.940 ;
    END
  END rd_data2[27]
  PIN rd_data2[28]
    DIRECTION OUTPUT ;
    USE SIGNAL ;
    SHAPE ABUTMENT ;
    PORT
      LAYER metal3 ;
      RECT 0.000 270.200 0.140 270.340 ;
    END
  END rd_data2[28]
  PIN rd_data2[29]
    DIRECTION OUTPUT ;
    USE SIGNAL ;
    SHAPE ABUTMENT ;
    PORT
      LAYER metal3 ;
      RECT 0.000 271.600 0.140 271.740 ;
    END
  END rd_data2[29]
  PIN rd_data2[30]
    DIRECTION OUTPUT ;
    USE SIGNAL ;
    SHAPE ABUTMENT ;
    PORT
      LAYER metal3 ;
      RECT 0.000 273.000 0.140 273.140 ;
    END
  END rd_data2[30]
  PIN rd_data2[31]
    DIRECTION OUTPUT ;
    USE SIGNAL ;
    SHAPE ABUTMENT ;
    PORT
      LAYER metal3 ;
      RECT 0.000 274.400 0.140 274.540 ;
    END
  END rd_data2[31]
  PIN VSS
    DIRECTION INOUT ;
    USE GROUND ;
    SHAPE ABUTMENT ;
    PORT
      LAYER metal3 ;
      RECT 0.000 275.800 62.510 275.940 ;
    END
  END VSS
  PIN VDD
    DIRECTION INOUT ;
    USE POWER ;
    SHAPE ABUTMENT ;
    PORT
      LAYER metal3 ;
      RECT 0.000 277.200 62.510 277.340 ;
    END
  END VDD
  OBS
    LAYER metal1 ;
      RECT 0.000 0.000 62.510 280.000 ;
    LAYER metal2 ;
      RECT 0.000 0.000 62.510 280.000 ;
    LAYER metal3 ;
      RECT 0.000 0.000 62.510 280.000 ;
    LAYER metal4 ;
      RECT 0.000 0.000 62.510 280.000 ;
  END
END vpu_64x32_3r2w_vpurf
END LIBRARY
